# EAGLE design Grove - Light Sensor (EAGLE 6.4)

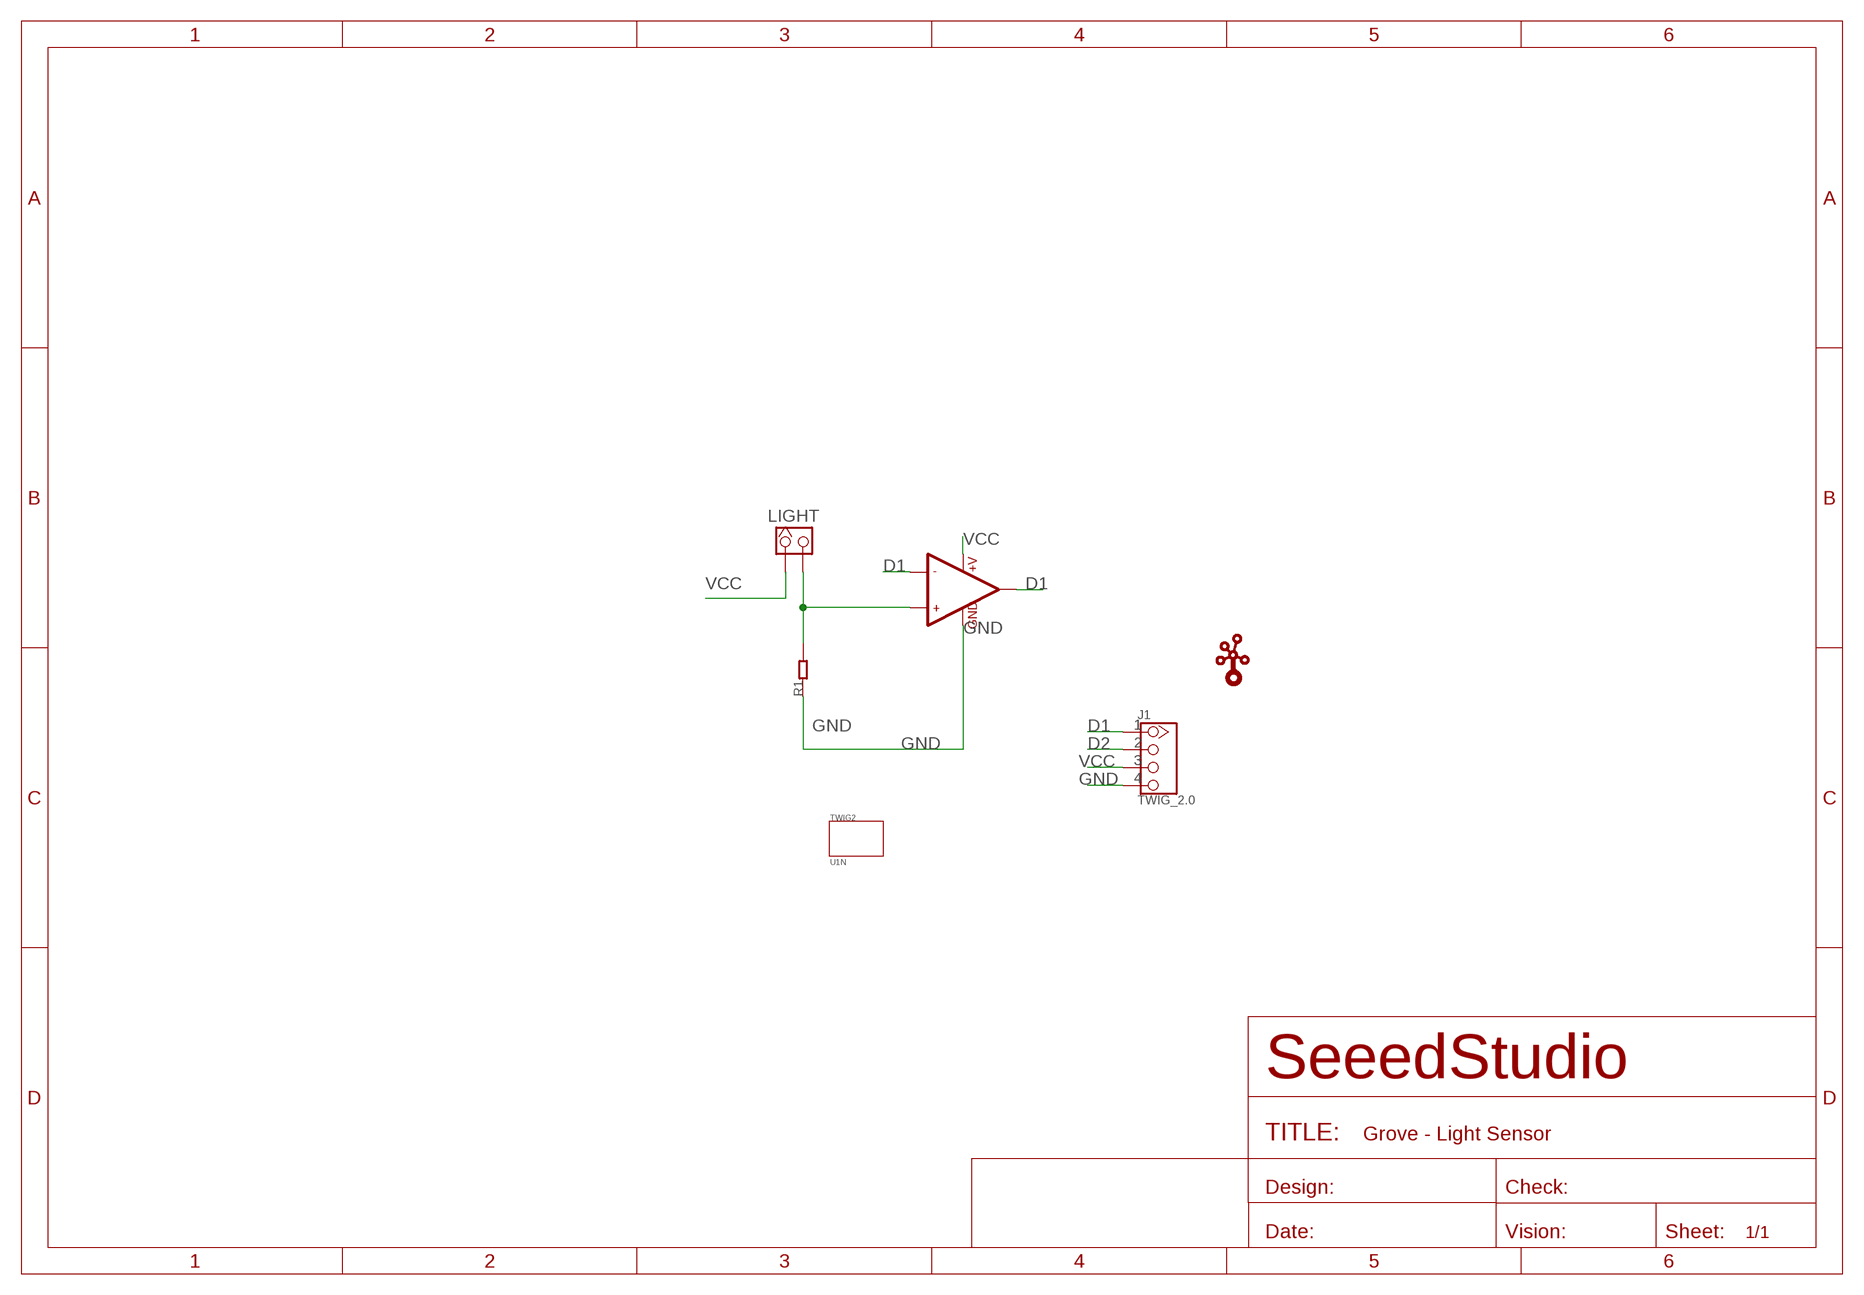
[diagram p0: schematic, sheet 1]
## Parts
J1  TWIG_2.0  TWIG_2.0F''  [2.0_1X4]
LIGHT  HEADER_1X2_2.54  [CK_1*2]
R1  R0603  [0603]
TWIG2  U1N  [U1N]
U1  LMV358  [SO08]
U$1  TWIGLOGOTWIGLOGO_SMALL  [TWIGLOGO_SMALL]

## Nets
D1: J1.1 U1.1(OUT1) U1.2(-IN1)
D2: J1.2
GND: J1.4 R1.1 U1.4(GND)
N$3: LIGHT.2 R1.2 U1.3(+IN1)
VCC: J1.3 LIGHT.1 U1.8(+V)
Unconnected: U1.5(+IN2) U1.6(-IN2) U1.7(OUT2)

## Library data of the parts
J1 = CONNECTER:TWIG_2.0
LIGHT = CONNECTER:HEADER_1X2
R1 = CPT_SMD:R0603
TWIG2 = twig_template1:U1N
U1 = ICs_v54:LMV358
U$1 = seeedleo:TWIGLOGO

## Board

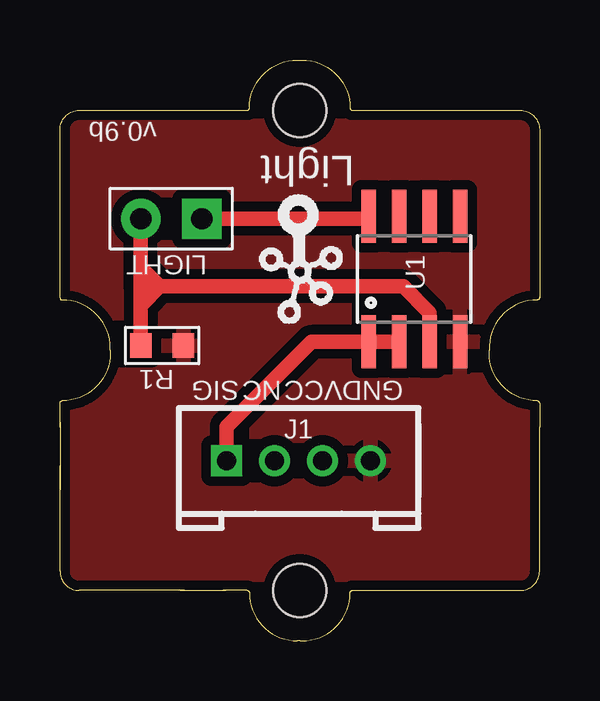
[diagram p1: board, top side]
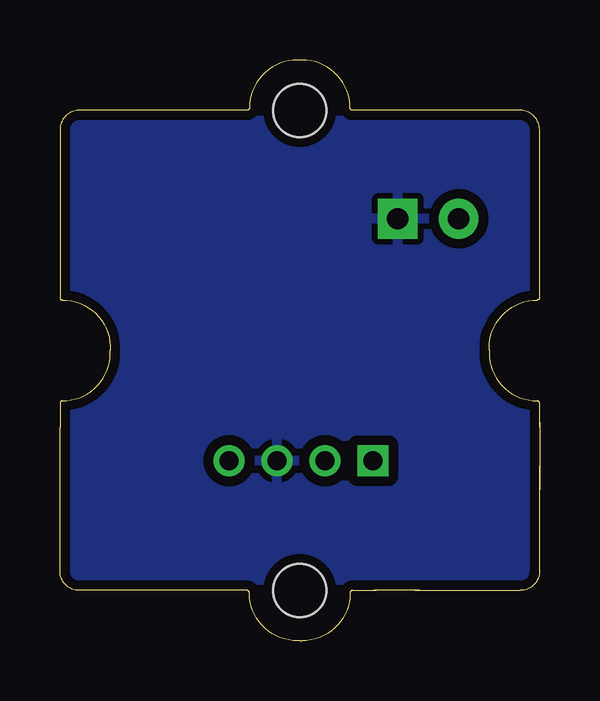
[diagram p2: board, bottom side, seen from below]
Size 20 x 24.2 mm. Coordinates in mm from the lower left corner, seen from the top.
Copper layers (1*16): Top 0.035mm / dielectric 1.5mm / Bottom 0.035mm
Design rules "SeeedStudio_rule_no_angle_090911": minimum track width 6mil, minimum drill 12mil, track to track 6mil, track to pad 6mil, pad to pad 6mil, via to via 6mil, smd to smd 0mil, copper to edge 10mil, drill to drill 10mil, minimum pad ring 10mil, minimum via ring 6mil, stop-mask expansion 2mil, vias tented up to drill 100mil, thermal gap 10mil

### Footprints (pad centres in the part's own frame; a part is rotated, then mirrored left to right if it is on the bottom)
2.0_1X4 = drill 0.8 pad 1.27 square: 1 -3,0 | drill 0.8 pad 1.27: 2 -1,0; 3 1,0; 4 3,0
CK_1*2 = drill 0.889 pad 1.651 square: 1 0,1.27 | drill 0.889 pad 1.651: 2 0,-1.27
0603 = smd 0.889 x 1.016: 1 -0.889,0; 2 0.889,0
U1N = hole 2.2: 0,-10; 0,10
SO08 = smd 0.61 x 2.21: 1 -1.905,-2.616; 2 -0.635,-2.616; 3 0.635,-2.616; 4 1.905,-2.616; 5 1.905,2.616; 6 0.635,2.616; 7 -0.635,2.616; 8 -1.905,2.616

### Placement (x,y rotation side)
J1  9.95,7.5 0 top
LIGHT  4.64,17.59 270 top
R1  4.26,12.3 180 top
TWIG2  10,12.1 0 top
U1  14.78,15.07 0 top
U$1  12.18,18.73 180 top

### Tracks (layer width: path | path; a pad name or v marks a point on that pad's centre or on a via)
D1
  Top 0.61: U1.2 U1.1 10.48,12.46 6.95,8.92 J1.1
GND
  pour Top (isolate 0.406): -2.06,25.31 22.45,25.31 22.45,-0.98 -2.06,-0.98
N$3
  Top 0.61: 3.37,14.64 LIGHT.2 | 3.37,14.64 R1.2 | 4.16,14.77 3.5,14.77 3.37,14.64 | 4.16,14.77 3.4,15.53 | 4.16,14.77 3.4,14.01 | U1.3 15.41,13.68 14.32,14.77 4.16,14.77
VCC
  Top 0.61: LIGHT.1 12.77,17.59 U1.8
  pour Bottom (isolate 0.406): -1.94,25.05 22.19,25.05 22.19,-0.98 -1.94,-0.98

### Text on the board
tPlace: v0.9b | Light | SIG | NC | VCC | GND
